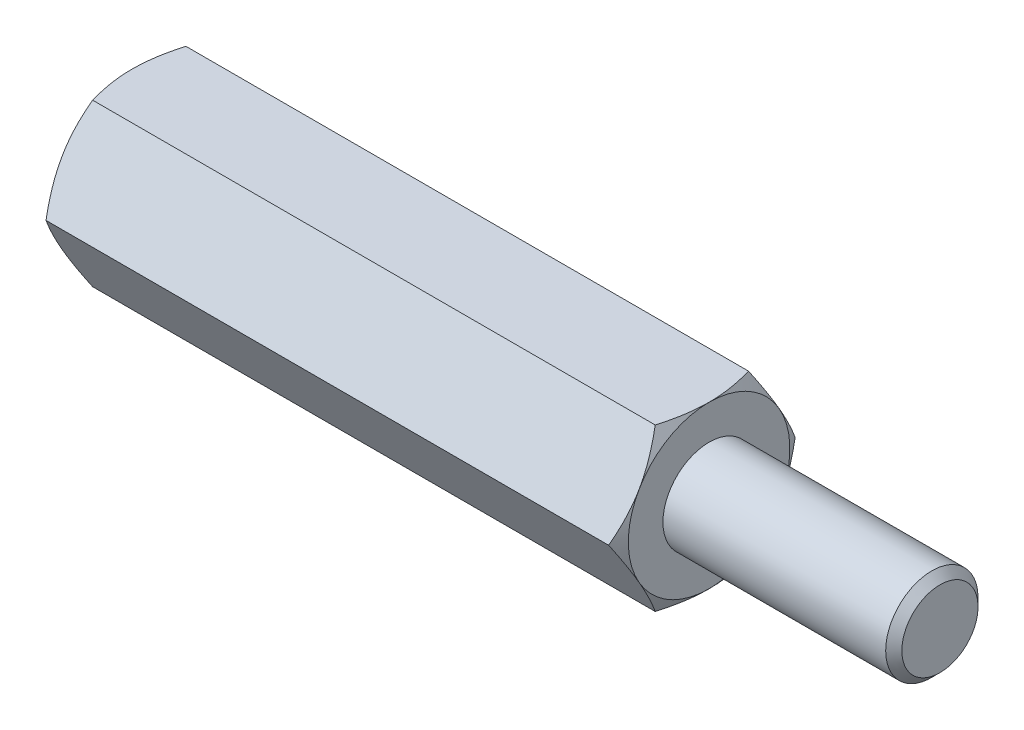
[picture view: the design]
ISO-10303-21;
HEADER;
FILE_DESCRIPTION(('STEP AP214'),'2;1');
FILE_NAME('part.step','',(''),(''),'','','');
FILE_SCHEMA(('AUTOMOTIVE_DESIGN { 1 0 10303 214 1 1 1 1 }'));
ENDSEC;
DATA;
#1=APPLICATION_CONTEXT('core data for automotive mechanical design processes');
#2=APPLICATION_PROTOCOL_DEFINITION('international standard','automotive_design',2000,#1);
#3=PRODUCT_CONTEXT('',#1,'mechanical');
#4=PRODUCT('Part','Part','',(#3));
#5=PRODUCT_RELATED_PRODUCT_CATEGORY('part','',(#4));
#6=PRODUCT_DEFINITION_FORMATION('','',#4);
#7=PRODUCT_DEFINITION_CONTEXT('part definition',#1,'design');
#8=PRODUCT_DEFINITION('design','',#6,#7);
#9=PRODUCT_DEFINITION_SHAPE('','',#8);
#10=(LENGTH_UNIT() NAMED_UNIT(*) SI_UNIT(.MILLI.,.METRE.));
#11=(NAMED_UNIT(*) PLANE_ANGLE_UNIT() SI_UNIT($,.RADIAN.));
#12=(NAMED_UNIT(*) SI_UNIT($,.STERADIAN.) SOLID_ANGLE_UNIT());
#13=UNCERTAINTY_MEASURE_WITH_UNIT(LENGTH_MEASURE(1.E-05),#10,'distance_accuracy_value','');
#14=(GEOMETRIC_REPRESENTATION_CONTEXT(3) GLOBAL_UNCERTAINTY_ASSIGNED_CONTEXT((#13)) GLOBAL_UNIT_ASSIGNED_CONTEXT((#10,
#11,#12)) REPRESENTATION_CONTEXT('',''));
#15=CARTESIAN_POINT('',(0.,0.,0.));
#16=DIRECTION('',(0.,0.,1.));
#17=DIRECTION('',(1.,0.,0.));
#18=AXIS2_PLACEMENT_3D('',#15,#16,#17);
#19=CARTESIAN_POINT('',(12.5,3.5,-2.02072594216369));
#20=DIRECTION('',(1.,0.,0.));
#21=DIRECTION('',(0.,0.,-1.));
#22=AXIS2_PLACEMENT_3D('',#19,#20,#21);
#23=PLANE('',#22);
#24=CARTESIAN_POINT('',(12.5,0.,0.));
#25=DIRECTION('',(1.,0.,0.));
#26=DIRECTION('',(0.,0.,-1.));
#27=AXIS2_PLACEMENT_3D('',#24,#25,#26);
#28=CIRCLE('',#27,3.5);
#29=CARTESIAN_POINT('',(12.5,-1.75,-3.03108891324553));
#30=VERTEX_POINT('',#29);
#31=CARTESIAN_POINT('',(12.5,1.75,-3.03108891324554));
#32=VERTEX_POINT('',#31);
#33=EDGE_CURVE('E288',#30,#32,#28,.T.);
#34=ORIENTED_EDGE('',*,*,#33,.T.);
#35=CARTESIAN_POINT('',(12.5,3.5,0.));
#36=VERTEX_POINT('',#35);
#37=EDGE_CURVE('E53',#32,#36,#28,.T.);
#38=ORIENTED_EDGE('',*,*,#37,.T.);
#39=CARTESIAN_POINT('',(12.5,1.75,3.03108891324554));
#40=VERTEX_POINT('',#39);
#41=EDGE_CURVE('E296',#36,#40,#28,.T.);
#42=ORIENTED_EDGE('',*,*,#41,.T.);
#43=CARTESIAN_POINT('',(12.5,-1.75000000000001,3.03108891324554));
#44=VERTEX_POINT('',#43);
#45=EDGE_CURVE('E301',#40,#44,#28,.T.);
#46=ORIENTED_EDGE('',*,*,#45,.T.);
#47=CARTESIAN_POINT('',(12.5,0.,0.));
#48=DIRECTION('',(-1.,0.,0.));
#49=DIRECTION('',(0.,-1.,0.));
#50=AXIS2_PLACEMENT_3D('',#47,#48,#49);
#51=CIRCLE('',#50,3.5);
#52=CARTESIAN_POINT('',(12.5,-3.5,0.));
#53=VERTEX_POINT('',#52);
#54=EDGE_CURVE('E193',#53,#44,#51,.T.);
#55=ORIENTED_EDGE('',*,*,#54,.F.);
#56=EDGE_CURVE('E61',#53,#30,#28,.T.);
#57=ORIENTED_EDGE('',*,*,#56,.T.);
#58=EDGE_LOOP('',(#34,#38,#42,#46,#55,#57));
#59=FACE_BOUND('',#58,.T.);
#60=CARTESIAN_POINT('',(12.5,0.,0.));
#61=DIRECTION('',(1.,0.,0.));
#62=DIRECTION('',(0.,0.,-1.));
#63=AXIS2_PLACEMENT_3D('',#60,#61,#62);
#64=CIRCLE('',#63,2.);
#65=CARTESIAN_POINT('',(12.5,0.,-2.));
#66=VERTEX_POINT('',#65);
#67=EDGE_CURVE('E393',#66,#66,#64,.T.);
#68=ORIENTED_EDGE('',*,*,#67,.F.);
#69=EDGE_LOOP('',(#68));
#70=FACE_BOUND('',#69,.T.);
#71=ADVANCED_FACE('F37',(#59,#70),#23,.T.);
#72=CARTESIAN_POINT('',(12.5,0.,-4.04145188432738));
#73=DIRECTION('',(0.,-0.5,0.866025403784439));
#74=DIRECTION('',(0.,-0.866025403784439,-0.5));
#75=AXIS2_PLACEMENT_3D('',#72,#73,#74);
#76=PLANE('',#75);
#77=CARTESIAN_POINT('',(12.1873259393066,-0.000200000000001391,-4.04156735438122));
#78=CARTESIAN_POINT('',(12.23861421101,0.153607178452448,-3.9527667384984));
#79=CARTESIAN_POINT('',(12.2852590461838,0.308742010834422,-3.86319960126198));
#80=CARTESIAN_POINT('',(12.3666781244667,0.621698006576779,-3.68251437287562));
#81=CARTESIAN_POINT('',(12.4014235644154,0.779524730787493,-3.59139307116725));
#82=CARTESIAN_POINT('',(12.4555099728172,1.09322221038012,-3.41027974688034));
#83=CARTESIAN_POINT('',(12.4752109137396,1.24904469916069,-3.32031559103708));
#84=CARTESIAN_POINT('',(12.4987298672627,1.56142288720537,-3.13996396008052));
#85=CARTESIAN_POINT('',(12.5025673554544,1.71797745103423,-3.04957714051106));
#86=CARTESIAN_POINT('',(12.494584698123,2.01050921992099,-2.88068384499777));
#87=CARTESIAN_POINT('',(12.4847245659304,2.1465302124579,-2.80215208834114));
#88=CARTESIAN_POINT('',(12.4534735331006,2.41768602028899,-2.64560020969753));
#89=CARTESIAN_POINT('',(12.4320719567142,2.55281989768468,-2.5675806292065));
#90=CARTESIAN_POINT('',(12.3785695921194,2.82453479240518,-2.41070596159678));
#91=CARTESIAN_POINT('',(12.3462420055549,2.96108141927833,-2.33187072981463));
#92=CARTESIAN_POINT('',(12.272871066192,3.2321380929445,-2.17537608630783));
#93=CARTESIAN_POINT('',(12.2318449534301,3.36665161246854,-2.09771466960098));
#94=CARTESIAN_POINT('',(12.1873259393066,3.5002,-2.02061047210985));
#95=B_SPLINE_CURVE_WITH_KNOTS('',3,(#77,#78,#79,#80,#81,#82,#83,#84,#85,#86,#87,#88,#89,#90,#91,
#92,#93,#94),.UNSPECIFIED.,.F.,.F.,(4,2,2,2,2,2,2,2,4),(0.,0.554793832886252,1.11092123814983,
1.65328467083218,2.19498204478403,2.6666513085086,3.13875761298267,3.6213361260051,
4.10296698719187),.UNSPECIFIED.);
#96=CARTESIAN_POINT('',(12.1873926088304,0.,-4.04145188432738));
#97=VERTEX_POINT('',#96);
#98=EDGE_CURVE('E314',#97,#32,#95,.T.);
#99=ORIENTED_EDGE('',*,*,#98,.F.);
#100=DIRECTION('',(-1.,0.,0.));
#101=VECTOR('',#100,1.);
#102=CARTESIAN_POINT('',(12.5,0.,-4.04145188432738));
#103=LINE('',#102,#101);
#104=CARTESIAN_POINT('',(-12.1873926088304,0.,-4.04145188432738));
#105=VERTEX_POINT('',#104);
#106=EDGE_CURVE('E264',#97,#105,#103,.T.);
#107=ORIENTED_EDGE('',*,*,#106,.T.);
#108=CARTESIAN_POINT('',(-12.1873259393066,3.5002,-2.02061047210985));
#109=CARTESIAN_POINT('',(-12.23861421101,3.34639282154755,-2.10941108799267));
#110=CARTESIAN_POINT('',(-12.2852590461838,3.19125798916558,-2.19897822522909));
#111=CARTESIAN_POINT('',(-12.3666781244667,2.87830199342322,-2.37966345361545));
#112=CARTESIAN_POINT('',(-12.4014235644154,2.72047526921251,-2.47078475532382));
#113=CARTESIAN_POINT('',(-12.4555099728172,2.40677778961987,-2.65189807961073));
#114=CARTESIAN_POINT('',(-12.4752109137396,2.25095530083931,-2.74186223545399));
#115=CARTESIAN_POINT('',(-12.4987298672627,1.93857711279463,-2.92221386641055));
#116=CARTESIAN_POINT('',(-12.5025673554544,1.78202254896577,-3.01260068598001));
#117=CARTESIAN_POINT('',(-12.494584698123,1.48949078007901,-3.1814939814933));
#118=CARTESIAN_POINT('',(-12.4847245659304,1.3534697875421,-3.26002573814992));
#119=CARTESIAN_POINT('',(-12.4534735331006,1.08231397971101,-3.41657761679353));
#120=CARTESIAN_POINT('',(-12.4320719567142,0.947180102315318,-3.49459719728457));
#121=CARTESIAN_POINT('',(-12.3785695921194,0.675465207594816,-3.65147186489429));
#122=CARTESIAN_POINT('',(-12.3462420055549,0.538918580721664,-3.73030709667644));
#123=CARTESIAN_POINT('',(-12.272871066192,0.267861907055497,-3.88680174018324));
#124=CARTESIAN_POINT('',(-12.2318449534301,0.133348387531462,-3.96446315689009));
#125=CARTESIAN_POINT('',(-12.1873259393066,-0.000200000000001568,-4.04156735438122));
#126=B_SPLINE_CURVE_WITH_KNOTS('',3,(#108,#109,#110,#111,#112,#113,#114,#115,#116,#117,#118,
#119,#120,#121,#122,#123,#124,#125),.UNSPECIFIED.,.F.,.F.,(4,2,2,2,2,2,2,2,4),(0.,
0.554793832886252,1.11092123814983,1.65328467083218,2.19498204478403,2.6666513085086,
3.13875761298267,3.6213361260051,4.10296698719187),.UNSPECIFIED.);
#127=CARTESIAN_POINT('',(-12.5,1.75,-3.03108891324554));
#128=VERTEX_POINT('',#127);
#129=EDGE_CURVE('E330',#128,#105,#126,.T.);
#130=ORIENTED_EDGE('',*,*,#129,.F.);
#131=CARTESIAN_POINT('',(-12.1873926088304,3.5,-2.02072594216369));
#132=VERTEX_POINT('',#131);
#133=EDGE_CURVE('E328',#132,#128,#126,.T.);
#134=ORIENTED_EDGE('',*,*,#133,.F.);
#135=DIRECTION('',(-1.,0.,0.));
#136=VECTOR('',#135,1.);
#137=CARTESIAN_POINT('',(12.5,3.5,-2.02072594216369));
#138=LINE('',#137,#136);
#139=CARTESIAN_POINT('',(12.1873926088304,3.5,-2.02072594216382));
#140=VERTEX_POINT('',#139);
#141=EDGE_CURVE('E279',#140,#132,#138,.T.);
#142=ORIENTED_EDGE('',*,*,#141,.F.);
#143=EDGE_CURVE('E229',#32,#140,#95,.T.);
#144=ORIENTED_EDGE('',*,*,#143,.F.);
#145=EDGE_LOOP('',(#99,#107,#130,#134,#142,#144));
#146=FACE_BOUND('',#145,.T.);
#147=ADVANCED_FACE('F148',(#146),#76,.F.);
#148=CARTESIAN_POINT('',(12.5,3.5,-2.02072594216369));
#149=DIRECTION('',(0.,-1.,0.));
#150=DIRECTION('',(0.,0.,-1.));
#151=AXIS2_PLACEMENT_3D('',#148,#149,#150);
#152=PLANE('',#151);
#153=CARTESIAN_POINT('',(10.7443294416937,3.5,-5.525713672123));
#154=CARTESIAN_POINT('',(10.8192813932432,3.5,-5.37200190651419));
#155=CARTESIAN_POINT('',(10.8935424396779,3.5,-5.21794762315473));
#156=CARTESIAN_POINT('',(11.0402960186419,3.5,-4.90897223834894));
#157=CARTESIAN_POINT('',(11.1127882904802,3.5,-4.75405101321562));
#158=CARTESIAN_POINT('',(11.2559617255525,3.5,-4.44240758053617));
#159=CARTESIAN_POINT('',(11.3266316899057,3.5,-4.28568021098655));
#160=CARTESIAN_POINT('',(11.4652074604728,3.5,-3.97101270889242));
#161=CARTESIAN_POINT('',(11.5331133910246,3.5,-3.81307263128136));
#162=CARTESIAN_POINT('',(11.6677143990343,3.5,-3.49026114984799));
#163=CARTESIAN_POINT('',(11.7342871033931,3.5,-3.32533845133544));
#164=CARTESIAN_POINT('',(11.8626267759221,3.5,-2.99359992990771));
#165=CARTESIAN_POINT('',(11.9243932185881,3.5,-2.82678390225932));
#166=CARTESIAN_POINT('',(12.0415700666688,3.5,-2.49127529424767));
#167=CARTESIAN_POINT('',(12.0969925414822,3.5,-2.32258697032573));
#168=CARTESIAN_POINT('',(12.1997679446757,3.5,-1.98279215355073));
#169=CARTESIAN_POINT('',(12.2471233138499,3.5,-1.81168640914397));
#170=CARTESIAN_POINT('',(12.3312987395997,3.5,-1.46793354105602));
#171=CARTESIAN_POINT('',(12.3681796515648,3.5,-1.2953015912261));
#172=CARTESIAN_POINT('',(12.4293955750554,3.5,-0.947791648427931));
#173=CARTESIAN_POINT('',(12.453731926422,3.5,-0.77291389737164));
#174=CARTESIAN_POINT('',(12.4876038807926,3.5,-0.424108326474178));
#175=CARTESIAN_POINT('',(12.497337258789,3.5,-0.250200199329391));
#176=CARTESIAN_POINT('',(12.5017053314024,3.5,0.0978233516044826));
#177=CARTESIAN_POINT('',(12.4963399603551,3.5,0.271938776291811));
#178=CARTESIAN_POINT('',(12.4750118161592,3.5,0.564711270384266));
#179=CARTESIAN_POINT('',(12.4628919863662,3.5,0.683667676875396));
#180=CARTESIAN_POINT('',(12.4323080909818,3.5,0.920767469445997));
#181=CARTESIAN_POINT('',(12.4138432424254,3.5,1.03891075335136));
#182=CARTESIAN_POINT('',(12.3498956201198,3.5,1.39193174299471));
#183=CARTESIAN_POINT('',(12.2958695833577,3.5,1.62528232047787));
#184=CARTESIAN_POINT('',(12.2014515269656,3.5,1.97433825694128));
#185=CARTESIAN_POINT('',(12.1672900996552,3.5,2.09183268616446));
#186=CARTESIAN_POINT('',(12.095234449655,3.5,2.32568238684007));
#187=CARTESIAN_POINT('',(12.0573401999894,3.5,2.44203765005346));
#188=CARTESIAN_POINT('',(11.9784421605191,3.5,2.67364238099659));
#189=CARTESIAN_POINT('',(11.9374392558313,3.5,2.78889215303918));
#190=CARTESIAN_POINT('',(11.852824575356,3.5,3.01842460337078));
#191=CARTESIAN_POINT('',(11.8092128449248,3.5,3.13270729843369));
#192=CARTESIAN_POINT('',(11.6958241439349,3.5,3.42150510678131));
#193=CARTESIAN_POINT('',(11.6245636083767,3.5,3.59543696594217));
#194=CARTESIAN_POINT('',(11.4781026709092,3.5,3.94163961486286));
#195=CARTESIAN_POINT('',(11.4029019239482,3.5,4.11391025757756));
#196=CARTESIAN_POINT('',(11.2494252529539,3.5,4.45713072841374));
#197=CARTESIAN_POINT('',(11.1711484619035,3.5,4.62808016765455));
#198=CARTESIAN_POINT('',(11.012188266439,3.5,4.9688584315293));
#199=CARTESIAN_POINT('',(10.9315047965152,3.5,5.13868722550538));
#200=CARTESIAN_POINT('',(10.6863871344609,3.5,5.64726192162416));
#201=CARTESIAN_POINT('',(10.5190975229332,3.5,5.98463020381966));
#202=CARTESIAN_POINT('',(10.1795854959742,3.5,6.65678495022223));
#203=CARTESIAN_POINT('',(10.0073639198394,3.5,6.99157184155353));
#204=CARTESIAN_POINT('',(9.67608002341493,3.5,7.62749570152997));
#205=CARTESIAN_POINT('',(9.51732992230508,3.5,7.92879562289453));
#206=CARTESIAN_POINT('',(9.19774734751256,3.5,8.53030635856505));
#207=CARTESIAN_POINT('',(9.03691477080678,3.5,8.83051711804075));
#208=CARTESIAN_POINT('',(8.71417926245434,3.5,9.42918006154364));
#209=CARTESIAN_POINT('',(8.5522810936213,3.5,9.72763481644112));
#210=CARTESIAN_POINT('',(8.2272737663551,3.5,10.3238577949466));
#211=CARTESIAN_POINT('',(8.06416469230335,3.5,10.6216260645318));
#212=CARTESIAN_POINT('',(7.90061041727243,3.5,10.9191478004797));
#213=B_SPLINE_CURVE_WITH_KNOTS('',3,(#153,#154,#155,#156,#157,#158,#159,#160,#161,#162,#163,
#164,#165,#166,#167,#168,#169,#170,#171,#172,#173,#174,#175,#176,#177,#178,#179,#180,#181,#182,
#183,#184,#185,#186,#187,#188,#189,#190,#191,#192,#193,#194,#195,#196,#197,#198,#199,#200,#201,
#202,#203,#204,#205,#206,#207,#208,#209,#210,#211,#212),.UNSPECIFIED.,.F.,.F.,(4,2,2,2,2,2,2,2,
2,2,2,2,2,2,2,2,2,2,2,2,2,2,2,2,2,2,2,2,2,4),(0.,0.513041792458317,1.02615874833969,
1.54190801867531,2.05763406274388,2.59113284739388,3.1246898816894,3.65721433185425,
4.18957737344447,4.71878103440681,5.24792816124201,5.76984197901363,6.29175806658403,
6.65030258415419,7.0088913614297,7.72642330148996,8.09346920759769,8.46051776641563,
8.82746220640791,9.19440026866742,9.7582223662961,10.3220939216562,10.8861255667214,
11.4501725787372,12.579801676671,13.7092396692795,14.730918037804,15.7526471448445,
16.771258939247,17.7898004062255),.UNSPECIFIED.);
#214=EDGE_CURVE('E227',#140,#36,#213,.T.);
#215=ORIENTED_EDGE('',*,*,#214,.F.);
#216=ORIENTED_EDGE('',*,*,#141,.T.);
#217=CARTESIAN_POINT('',(-10.7443294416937,3.5,-5.52571367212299));
#218=CARTESIAN_POINT('',(-10.8192813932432,3.5,-5.37200190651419));
#219=CARTESIAN_POINT('',(-10.8935424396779,3.5,-5.21794762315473));
#220=CARTESIAN_POINT('',(-11.0402960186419,3.5,-4.90897223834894));
#221=CARTESIAN_POINT('',(-11.1127882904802,3.5,-4.75405101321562));
#222=CARTESIAN_POINT('',(-11.2559617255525,3.5,-4.44240758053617));
#223=CARTESIAN_POINT('',(-11.3266316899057,3.5,-4.28568021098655));
#224=CARTESIAN_POINT('',(-11.4652074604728,3.5,-3.97101270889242));
#225=CARTESIAN_POINT('',(-11.5331133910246,3.5,-3.81307263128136));
#226=CARTESIAN_POINT('',(-11.6677143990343,3.5,-3.49026114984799));
#227=CARTESIAN_POINT('',(-11.7342871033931,3.5,-3.32533845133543));
#228=CARTESIAN_POINT('',(-11.8626267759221,3.5,-2.99359992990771));
#229=CARTESIAN_POINT('',(-11.9243932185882,3.5,-2.82678390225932));
#230=CARTESIAN_POINT('',(-12.0415700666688,3.5,-2.49127529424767));
#231=CARTESIAN_POINT('',(-12.0969925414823,3.5,-2.32258697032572));
#232=CARTESIAN_POINT('',(-12.1997679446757,3.5,-1.98279215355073));
#233=CARTESIAN_POINT('',(-12.2471233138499,3.5,-1.81168640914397));
#234=CARTESIAN_POINT('',(-12.3312987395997,3.5,-1.46793354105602));
#235=CARTESIAN_POINT('',(-12.3681796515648,3.5,-1.2953015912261));
#236=CARTESIAN_POINT('',(-12.4293955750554,3.5,-0.94779164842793));
#237=CARTESIAN_POINT('',(-12.453731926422,3.5,-0.772913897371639));
#238=CARTESIAN_POINT('',(-12.4876038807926,3.5,-0.424108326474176));
#239=CARTESIAN_POINT('',(-12.497337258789,3.5,-0.250200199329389));
#240=CARTESIAN_POINT('',(-12.5017053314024,3.5,0.0978233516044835));
#241=CARTESIAN_POINT('',(-12.4963399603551,3.5,0.271938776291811));
#242=CARTESIAN_POINT('',(-12.4750118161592,3.5,0.564711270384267));
#243=CARTESIAN_POINT('',(-12.4628919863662,3.5,0.683667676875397));
#244=CARTESIAN_POINT('',(-12.4323080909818,3.5,0.920767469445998));
#245=CARTESIAN_POINT('',(-12.4138432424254,3.5,1.03891075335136));
#246=CARTESIAN_POINT('',(-12.3498956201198,3.5,1.39193174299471));
#247=CARTESIAN_POINT('',(-12.2958695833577,3.5,1.62528232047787));
#248=CARTESIAN_POINT('',(-12.2014515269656,3.5,1.97433825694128));
#249=CARTESIAN_POINT('',(-12.1672900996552,3.5,2.09183268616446));
#250=CARTESIAN_POINT('',(-12.095234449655,3.5,2.32568238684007));
#251=CARTESIAN_POINT('',(-12.0573401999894,3.5,2.44203765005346));
#252=CARTESIAN_POINT('',(-11.9784421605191,3.5,2.67364238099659));
#253=CARTESIAN_POINT('',(-11.9374392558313,3.5,2.78889215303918));
#254=CARTESIAN_POINT('',(-11.852824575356,3.5,3.01842460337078));
#255=CARTESIAN_POINT('',(-11.8092128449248,3.5,3.13270729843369));
#256=CARTESIAN_POINT('',(-11.6958241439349,3.5,3.42150510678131));
#257=CARTESIAN_POINT('',(-11.6245636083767,3.5,3.59543696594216));
#258=CARTESIAN_POINT('',(-11.4781026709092,3.5,3.94163961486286));
#259=CARTESIAN_POINT('',(-11.4029019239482,3.5,4.11391025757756));
#260=CARTESIAN_POINT('',(-11.2494252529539,3.5,4.45713072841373));
#261=CARTESIAN_POINT('',(-11.1711484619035,3.5,4.62808016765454));
#262=CARTESIAN_POINT('',(-11.012188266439,3.5,4.96885843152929));
#263=CARTESIAN_POINT('',(-10.9315047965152,3.5,5.13868722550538));
#264=CARTESIAN_POINT('',(-10.6863871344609,3.5,5.64726192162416));
#265=CARTESIAN_POINT('',(-10.5190975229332,3.5,5.98463020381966));
#266=CARTESIAN_POINT('',(-10.1795854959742,3.5,6.65678495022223));
#267=CARTESIAN_POINT('',(-10.0073639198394,3.5,6.99157184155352));
#268=CARTESIAN_POINT('',(-9.67608002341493,3.5,7.62749570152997));
#269=CARTESIAN_POINT('',(-9.51732992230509,3.5,7.92879562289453));
#270=CARTESIAN_POINT('',(-9.19774734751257,3.5,8.53030635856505));
#271=CARTESIAN_POINT('',(-9.03691477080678,3.5,8.83051711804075));
#272=CARTESIAN_POINT('',(-8.71417926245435,3.5,9.42918006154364));
#273=CARTESIAN_POINT('',(-8.5522810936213,3.5,9.72763481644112));
#274=CARTESIAN_POINT('',(-8.2272737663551,3.5,10.3238577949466));
#275=CARTESIAN_POINT('',(-8.06416469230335,3.5,10.6216260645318));
#276=CARTESIAN_POINT('',(-7.90061041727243,3.5,10.9191478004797));
#277=B_SPLINE_CURVE_WITH_KNOTS('',3,(#217,#218,#219,#220,#221,#222,#223,#224,#225,#226,#227,
#228,#229,#230,#231,#232,#233,#234,#235,#236,#237,#238,#239,#240,#241,#242,#243,#244,#245,#246,
#247,#248,#249,#250,#251,#252,#253,#254,#255,#256,#257,#258,#259,#260,#261,#262,#263,#264,#265,
#266,#267,#268,#269,#270,#271,#272,#273,#274,#275,#276),.UNSPECIFIED.,.F.,.F.,(4,2,2,2,2,2,2,2,
2,2,2,2,2,2,2,2,2,2,2,2,2,2,2,2,2,2,2,2,2,4),(0.,0.513041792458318,1.02615874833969,
1.54190801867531,2.05763406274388,2.59113284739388,3.1246898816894,3.65721433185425,
4.18957737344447,4.71878103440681,5.24792816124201,5.76984197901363,6.29175806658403,
6.65030258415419,7.0088913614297,7.72642330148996,8.09346920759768,8.46051776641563,
8.8274622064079,9.19440026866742,9.75822236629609,10.3220939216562,10.8861255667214,
11.4501725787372,12.579801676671,13.7092396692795,14.730918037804,15.7526471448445,
16.7712589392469,17.7898004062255),.UNSPECIFIED.);
#278=CARTESIAN_POINT('',(-12.5,3.5,0.));
#279=VERTEX_POINT('',#278);
#280=EDGE_CURVE('E241',#279,#132,#277,.F.);
#281=ORIENTED_EDGE('',*,*,#280,.F.);
#282=CARTESIAN_POINT('',(-12.1873926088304,3.5,2.02072594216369));
#283=VERTEX_POINT('',#282);
#284=EDGE_CURVE('E249',#283,#279,#277,.F.);
#285=ORIENTED_EDGE('',*,*,#284,.F.);
#286=DIRECTION('',(-1.,0.,0.));
#287=VECTOR('',#286,1.);
#288=CARTESIAN_POINT('',(12.5,3.5,2.02072594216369));
#289=LINE('',#288,#287);
#290=CARTESIAN_POINT('',(12.1873926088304,3.5,2.02072594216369));
#291=VERTEX_POINT('',#290);
#292=EDGE_CURVE('E276',#291,#283,#289,.T.);
#293=ORIENTED_EDGE('',*,*,#292,.F.);
#294=EDGE_CURVE('E221',#36,#291,#213,.T.);
#295=ORIENTED_EDGE('',*,*,#294,.F.);
#296=EDGE_LOOP('',(#215,#216,#281,#285,#293,#295));
#297=FACE_BOUND('',#296,.T.);
#298=ADVANCED_FACE('F153',(#297),#152,.F.);
#299=CARTESIAN_POINT('',(12.5,3.5,2.02072594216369));
#300=DIRECTION('',(0.,-0.5,-0.866025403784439));
#301=DIRECTION('',(0.,0.866025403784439,-0.5));
#302=AXIS2_PLACEMENT_3D('',#299,#300,#301);
#303=PLANE('',#302);
#304=CARTESIAN_POINT('',(12.1873259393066,3.5002,2.02061047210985));
#305=CARTESIAN_POINT('',(12.23861421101,3.34639282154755,2.10941108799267));
#306=CARTESIAN_POINT('',(12.2852590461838,3.19125798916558,2.19897822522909));
#307=CARTESIAN_POINT('',(12.3666781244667,2.87830199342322,2.37966345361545));
#308=CARTESIAN_POINT('',(12.4014235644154,2.7204752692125,2.47078475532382));
#309=CARTESIAN_POINT('',(12.4555099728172,2.40677778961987,2.65189807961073));
#310=CARTESIAN_POINT('',(12.4752109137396,2.25095530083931,2.74186223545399));
#311=CARTESIAN_POINT('',(12.4987298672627,1.93857711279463,2.92221386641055));
#312=CARTESIAN_POINT('',(12.5025673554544,1.78202254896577,3.01260068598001));
#313=CARTESIAN_POINT('',(12.494584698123,1.48949078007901,3.1814939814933));
#314=CARTESIAN_POINT('',(12.4847245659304,1.35346978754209,3.26002573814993));
#315=CARTESIAN_POINT('',(12.4534735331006,1.08231397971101,3.41657761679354));
#316=CARTESIAN_POINT('',(12.4320719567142,0.947180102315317,3.49459719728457));
#317=CARTESIAN_POINT('',(12.3785695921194,0.675465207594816,3.65147186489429));
#318=CARTESIAN_POINT('',(12.3462420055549,0.538918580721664,3.73030709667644));
#319=CARTESIAN_POINT('',(12.272871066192,0.267861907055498,3.88680174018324));
#320=CARTESIAN_POINT('',(12.2318449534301,0.133348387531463,3.96446315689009));
#321=CARTESIAN_POINT('',(12.1873259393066,-0.000200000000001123,4.04156735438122));
#322=B_SPLINE_CURVE_WITH_KNOTS('',3,(#304,#305,#306,#307,#308,#309,#310,#311,#312,#313,#314,
#315,#316,#317,#318,#319,#320,#321),.UNSPECIFIED.,.F.,.F.,(4,2,2,2,2,2,2,2,4),(0.,
0.554793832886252,1.11092123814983,1.65328467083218,2.19498204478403,2.6666513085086,
3.13875761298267,3.62133612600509,4.10296698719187),.UNSPECIFIED.);
#323=EDGE_CURVE('E228',#291,#40,#322,.T.);
#324=ORIENTED_EDGE('',*,*,#323,.F.);
#325=ORIENTED_EDGE('',*,*,#292,.T.);
#326=CARTESIAN_POINT('',(-12.1873259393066,-0.000200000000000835,4.04156735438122));
#327=CARTESIAN_POINT('',(-12.23861421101,0.153607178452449,3.9527667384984));
#328=CARTESIAN_POINT('',(-12.2852590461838,0.308742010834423,3.86319960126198));
#329=CARTESIAN_POINT('',(-12.3666781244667,0.62169800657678,3.68251437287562));
#330=CARTESIAN_POINT('',(-12.4014235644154,0.779524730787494,3.59139307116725));
#331=CARTESIAN_POINT('',(-12.4555099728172,1.09322221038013,3.41027974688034));
#332=CARTESIAN_POINT('',(-12.4752109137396,1.24904469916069,3.32031559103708));
#333=CARTESIAN_POINT('',(-12.4987298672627,1.56142288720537,3.13996396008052));
#334=CARTESIAN_POINT('',(-12.5025673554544,1.71797745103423,3.04957714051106));
#335=CARTESIAN_POINT('',(-12.494584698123,2.01050921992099,2.88068384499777));
#336=CARTESIAN_POINT('',(-12.4847245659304,2.1465302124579,2.80215208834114));
#337=CARTESIAN_POINT('',(-12.4534735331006,2.41768602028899,2.64560020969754));
#338=CARTESIAN_POINT('',(-12.4320719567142,2.55281989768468,2.5675806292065));
#339=CARTESIAN_POINT('',(-12.3785695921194,2.82453479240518,2.41070596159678));
#340=CARTESIAN_POINT('',(-12.3462420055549,2.96108141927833,2.33187072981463));
#341=CARTESIAN_POINT('',(-12.272871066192,3.2321380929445,2.17537608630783));
#342=CARTESIAN_POINT('',(-12.2318449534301,3.36665161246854,2.09771466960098));
#343=CARTESIAN_POINT('',(-12.1873259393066,3.5002,2.02061047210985));
#344=B_SPLINE_CURVE_WITH_KNOTS('',3,(#326,#327,#328,#329,#330,#331,#332,#333,#334,#335,#336,
#337,#338,#339,#340,#341,#342,#343),.UNSPECIFIED.,.F.,.F.,(4,2,2,2,2,2,2,2,4),(0.,
0.554793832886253,1.11092123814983,1.65328467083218,2.19498204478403,2.6666513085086,
3.13875761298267,3.62133612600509,4.10296698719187),.UNSPECIFIED.);
#345=CARTESIAN_POINT('',(-12.5,1.75,3.03108891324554));
#346=VERTEX_POINT('',#345);
#347=EDGE_CURVE('E255',#346,#283,#344,.T.);
#348=ORIENTED_EDGE('',*,*,#347,.F.);
#349=CARTESIAN_POINT('',(-12.1873926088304,0.,4.04145188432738));
#350=VERTEX_POINT('',#349);
#351=EDGE_CURVE('E262',#350,#346,#344,.T.);
#352=ORIENTED_EDGE('',*,*,#351,.F.);
#353=DIRECTION('',(-1.,0.,0.));
#354=VECTOR('',#353,1.);
#355=CARTESIAN_POINT('',(12.5,0.,4.04145188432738));
#356=LINE('',#355,#354);
#357=CARTESIAN_POINT('',(12.1873926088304,0.,4.04145188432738));
#358=VERTEX_POINT('',#357);
#359=EDGE_CURVE('E273',#358,#350,#356,.T.);
#360=ORIENTED_EDGE('',*,*,#359,.F.);
#361=EDGE_CURVE('E215',#40,#358,#322,.T.);
#362=ORIENTED_EDGE('',*,*,#361,.F.);
#363=EDGE_LOOP('',(#324,#325,#348,#352,#360,#362));
#364=FACE_BOUND('',#363,.T.);
#365=ADVANCED_FACE('F235',(#364),#303,.F.);
#366=CARTESIAN_POINT('',(12.5,0.,4.04145188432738));
#367=DIRECTION('',(0.,0.5,-0.866025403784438));
#368=DIRECTION('',(0.,0.866025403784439,0.5));
#369=AXIS2_PLACEMENT_3D('',#366,#367,#368);
#370=PLANE('',#369);
#371=CARTESIAN_POINT('',(12.1873259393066,0.000199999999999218,4.04156735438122));
#372=CARTESIAN_POINT('',(12.23861421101,-0.15360717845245,3.9527667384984));
#373=CARTESIAN_POINT('',(12.2852590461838,-0.308742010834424,3.86319960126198));
#374=CARTESIAN_POINT('',(12.3666781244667,-0.621698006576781,3.68251437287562));
#375=CARTESIAN_POINT('',(12.4014235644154,-0.779524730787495,3.59139307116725));
#376=CARTESIAN_POINT('',(12.4555099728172,-1.09322221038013,3.41027974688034));
#377=CARTESIAN_POINT('',(12.4752109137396,-1.24904469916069,3.32031559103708));
#378=CARTESIAN_POINT('',(12.4987298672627,-1.56142288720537,3.13996396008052));
#379=CARTESIAN_POINT('',(12.5025673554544,-1.71797745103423,3.04957714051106));
#380=CARTESIAN_POINT('',(12.494584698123,-2.01050921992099,2.88068384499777));
#381=CARTESIAN_POINT('',(12.4847245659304,-2.1465302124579,2.80215208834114));
#382=CARTESIAN_POINT('',(12.4534735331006,-2.41768602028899,2.64560020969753));
#383=CARTESIAN_POINT('',(12.4320719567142,-2.55281989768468,2.5675806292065));
#384=CARTESIAN_POINT('',(12.3785695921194,-2.82453479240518,2.41070596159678));
#385=CARTESIAN_POINT('',(12.3462420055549,-2.96108141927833,2.33187072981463));
#386=CARTESIAN_POINT('',(12.272871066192,-3.2321380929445,2.17537608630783));
#387=CARTESIAN_POINT('',(12.2318449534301,-3.36665161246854,2.09771466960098));
#388=CARTESIAN_POINT('',(12.1873259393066,-3.5002,2.02061047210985));
#389=B_SPLINE_CURVE_WITH_KNOTS('',3,(#371,#372,#373,#374,#375,#376,#377,#378,#379,#380,#381,
#382,#383,#384,#385,#386,#387,#388),.UNSPECIFIED.,.F.,.F.,(4,2,2,2,2,2,2,2,4),(0.,
0.554793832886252,1.11092123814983,1.65328467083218,2.19498204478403,2.6666513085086,
3.13875761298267,3.62133612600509,4.10296698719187),.UNSPECIFIED.);
#390=EDGE_CURVE('E318',#358,#44,#389,.T.);
#391=ORIENTED_EDGE('',*,*,#390,.F.);
#392=ORIENTED_EDGE('',*,*,#359,.T.);
#393=CARTESIAN_POINT('',(-12.1873259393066,-3.5002,2.02061047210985));
#394=CARTESIAN_POINT('',(-12.23861421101,-3.34639282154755,2.10941108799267));
#395=CARTESIAN_POINT('',(-12.2852590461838,-3.19125798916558,2.19897822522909));
#396=CARTESIAN_POINT('',(-12.3666781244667,-2.87830199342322,2.37966345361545));
#397=CARTESIAN_POINT('',(-12.4014235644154,-2.72047526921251,2.47078475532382));
#398=CARTESIAN_POINT('',(-12.4555099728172,-2.40677778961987,2.65189807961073));
#399=CARTESIAN_POINT('',(-12.4752109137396,-2.25095530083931,2.74186223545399));
#400=CARTESIAN_POINT('',(-12.4987298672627,-1.93857711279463,2.92221386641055));
#401=CARTESIAN_POINT('',(-12.5025673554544,-1.78202254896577,3.01260068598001));
#402=CARTESIAN_POINT('',(-12.494584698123,-1.48949078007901,3.1814939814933));
#403=CARTESIAN_POINT('',(-12.4847245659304,-1.3534697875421,3.26002573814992));
#404=CARTESIAN_POINT('',(-12.4534735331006,-1.08231397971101,3.41657761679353));
#405=CARTESIAN_POINT('',(-12.4320719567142,-0.94718010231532,3.49459719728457));
#406=CARTESIAN_POINT('',(-12.3785695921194,-0.675465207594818,3.65147186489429));
#407=CARTESIAN_POINT('',(-12.3462420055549,-0.538918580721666,3.73030709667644));
#408=CARTESIAN_POINT('',(-12.272871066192,-0.2678619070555,3.88680174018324));
#409=CARTESIAN_POINT('',(-12.2318449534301,-0.133348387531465,3.96446315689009));
#410=CARTESIAN_POINT('',(-12.1873259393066,0.000199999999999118,4.04156735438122));
#411=B_SPLINE_CURVE_WITH_KNOTS('',3,(#393,#394,#395,#396,#397,#398,#399,#400,#401,#402,#403,
#404,#405,#406,#407,#408,#409,#410),.UNSPECIFIED.,.F.,.F.,(4,2,2,2,2,2,2,2,4),(0.,
0.554793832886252,1.11092123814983,1.65328467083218,2.19498204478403,2.6666513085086,
3.13875761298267,3.62133612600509,4.10296698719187),.UNSPECIFIED.);
#412=CARTESIAN_POINT('',(-12.5,-1.75000000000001,3.03108891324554));
#413=VERTEX_POINT('',#412);
#414=EDGE_CURVE('E263',#413,#350,#411,.T.);
#415=ORIENTED_EDGE('',*,*,#414,.F.);
#416=CARTESIAN_POINT('',(-12.1873926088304,-3.5,2.02072594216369));
#417=VERTEX_POINT('',#416);
#418=EDGE_CURVE('E250',#417,#413,#411,.T.);
#419=ORIENTED_EDGE('',*,*,#418,.F.);
#420=DIRECTION('',(-1.,0.,0.));
#421=VECTOR('',#420,1.);
#422=CARTESIAN_POINT('',(12.5,-3.5,2.02072594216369));
#423=LINE('',#422,#421);
#424=CARTESIAN_POINT('',(12.1873926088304,-3.5,2.02072594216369));
#425=VERTEX_POINT('',#424);
#426=EDGE_CURVE('E270',#425,#417,#423,.T.);
#427=ORIENTED_EDGE('',*,*,#426,.F.);
#428=EDGE_CURVE('E210',#44,#425,#389,.T.);
#429=ORIENTED_EDGE('',*,*,#428,.F.);
#430=EDGE_LOOP('',(#391,#392,#415,#419,#427,#429));
#431=FACE_BOUND('',#430,.T.);
#432=ADVANCED_FACE('F425',(#431),#370,.F.);
#433=CARTESIAN_POINT('',(12.5,-3.5,2.02072594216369));
#434=DIRECTION('',(0.,1.,0.));
#435=DIRECTION('',(0.,0.,1.));
#436=AXIS2_PLACEMENT_3D('',#433,#434,#435);
#437=PLANE('',#436);
#438=CARTESIAN_POINT('',(10.7443294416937,-3.5,-5.52571367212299));
#439=CARTESIAN_POINT('',(10.8192813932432,-3.5,-5.37200190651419));
#440=CARTESIAN_POINT('',(10.8935424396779,-3.5,-5.21794762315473));
#441=CARTESIAN_POINT('',(11.0402960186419,-3.5,-4.90897223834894));
#442=CARTESIAN_POINT('',(11.1127882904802,-3.5,-4.75405101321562));
#443=CARTESIAN_POINT('',(11.2559617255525,-3.5,-4.44240758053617));
#444=CARTESIAN_POINT('',(11.3266316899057,-3.5,-4.28568021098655));
#445=CARTESIAN_POINT('',(11.4652074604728,-3.5,-3.97101270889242));
#446=CARTESIAN_POINT('',(11.5331133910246,-3.5,-3.81307263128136));
#447=CARTESIAN_POINT('',(11.6677143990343,-3.5,-3.49026114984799));
#448=CARTESIAN_POINT('',(11.7342871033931,-3.5,-3.32533845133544));
#449=CARTESIAN_POINT('',(11.8626267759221,-3.5,-2.99359992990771));
#450=CARTESIAN_POINT('',(11.9243932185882,-3.5,-2.82678390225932));
#451=CARTESIAN_POINT('',(12.0415700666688,-3.5,-2.49127529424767));
#452=CARTESIAN_POINT('',(12.0969925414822,-3.5,-2.32258697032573));
#453=CARTESIAN_POINT('',(12.1997679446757,-3.5,-1.98279215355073));
#454=CARTESIAN_POINT('',(12.2471233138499,-3.5,-1.81168640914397));
#455=CARTESIAN_POINT('',(12.3312987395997,-3.5,-1.46793354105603));
#456=CARTESIAN_POINT('',(12.3681796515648,-3.5,-1.2953015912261));
#457=CARTESIAN_POINT('',(12.4293955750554,-3.5,-0.947791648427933));
#458=CARTESIAN_POINT('',(12.453731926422,-3.5,-0.772913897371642));
#459=CARTESIAN_POINT('',(12.4876038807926,-3.5,-0.424108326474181));
#460=CARTESIAN_POINT('',(12.497337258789,-3.5,-0.250200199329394));
#461=CARTESIAN_POINT('',(12.5017053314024,-3.5,0.0978233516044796));
#462=CARTESIAN_POINT('',(12.4963399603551,-3.5,0.271938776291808));
#463=CARTESIAN_POINT('',(12.4750118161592,-3.5,0.564711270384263));
#464=CARTESIAN_POINT('',(12.4628919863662,-3.5,0.683667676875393));
#465=CARTESIAN_POINT('',(12.4323080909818,-3.5,0.920767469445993));
#466=CARTESIAN_POINT('',(12.4138432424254,-3.5,1.03891075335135));
#467=CARTESIAN_POINT('',(12.3498956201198,-3.5,1.3919317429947));
#468=CARTESIAN_POINT('',(12.2958695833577,-3.5,1.62528232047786));
#469=CARTESIAN_POINT('',(12.2014515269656,-3.5,1.97433825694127));
#470=CARTESIAN_POINT('',(12.1672900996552,-3.5,2.09183268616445));
#471=CARTESIAN_POINT('',(12.095234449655,-3.5,2.32568238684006));
#472=CARTESIAN_POINT('',(12.0573401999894,-3.5,2.44203765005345));
#473=CARTESIAN_POINT('',(11.9784421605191,-3.5,2.67364238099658));
#474=CARTESIAN_POINT('',(11.9374392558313,-3.5,2.78889215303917));
#475=CARTESIAN_POINT('',(11.852824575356,-3.5,3.01842460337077));
#476=CARTESIAN_POINT('',(11.8092128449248,-3.5,3.13270729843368));
#477=CARTESIAN_POINT('',(11.6958241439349,-3.5,3.4215051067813));
#478=CARTESIAN_POINT('',(11.6245636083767,-3.5,3.59543696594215));
#479=CARTESIAN_POINT('',(11.4781026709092,-3.5,3.94163961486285));
#480=CARTESIAN_POINT('',(11.4029019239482,-3.5,4.11391025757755));
#481=CARTESIAN_POINT('',(11.2494252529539,-3.5,4.45713072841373));
#482=CARTESIAN_POINT('',(11.1711484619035,-3.5,4.62808016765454));
#483=CARTESIAN_POINT('',(11.0121882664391,-3.5,4.96885843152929));
#484=CARTESIAN_POINT('',(10.9315047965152,-3.5,5.13868722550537));
#485=CARTESIAN_POINT('',(10.6863871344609,-3.5,5.64726192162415));
#486=CARTESIAN_POINT('',(10.5190975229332,-3.5,5.98463020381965));
#487=CARTESIAN_POINT('',(10.1795854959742,-3.5,6.65678495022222));
#488=CARTESIAN_POINT('',(10.0073639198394,-3.5,6.99157184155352));
#489=CARTESIAN_POINT('',(9.67608002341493,-3.5,7.62749570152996));
#490=CARTESIAN_POINT('',(9.51732992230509,-3.5,7.92879562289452));
#491=CARTESIAN_POINT('',(9.19774734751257,-3.5,8.53030635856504));
#492=CARTESIAN_POINT('',(9.03691477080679,-3.5,8.83051711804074));
#493=CARTESIAN_POINT('',(8.71417926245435,-3.5,9.42918006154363));
#494=CARTESIAN_POINT('',(8.5522810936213,-3.5,9.72763481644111));
#495=CARTESIAN_POINT('',(8.22727376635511,-3.5,10.3238577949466));
#496=CARTESIAN_POINT('',(8.06416469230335,-3.5,10.6216260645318));
#497=CARTESIAN_POINT('',(7.90061041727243,-3.5,10.9191478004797));
#498=B_SPLINE_CURVE_WITH_KNOTS('',3,(#438,#439,#440,#441,#442,#443,#444,#445,#446,#447,#448,
#449,#450,#451,#452,#453,#454,#455,#456,#457,#458,#459,#460,#461,#462,#463,#464,#465,#466,#467,
#468,#469,#470,#471,#472,#473,#474,#475,#476,#477,#478,#479,#480,#481,#482,#483,#484,#485,#486,
#487,#488,#489,#490,#491,#492,#493,#494,#495,#496,#497),.UNSPECIFIED.,.F.,.F.,(4,2,2,2,2,2,2,2,
2,2,2,2,2,2,2,2,2,2,2,2,2,2,2,2,2,2,2,2,2,4),(0.,0.513041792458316,1.02615874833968,
1.5419080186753,2.05763406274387,2.59113284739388,3.1246898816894,3.65721433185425,
4.18957737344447,4.71878103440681,5.247928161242,5.76984197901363,6.29175806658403,
6.65030258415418,7.0088913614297,7.72642330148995,8.09346920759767,8.46051776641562,
8.82746220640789,9.1944002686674,9.75822236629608,10.3220939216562,10.8861255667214,
11.4501725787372,12.579801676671,13.7092396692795,14.730918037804,15.7526471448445,
16.7712589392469,17.7898004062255),.UNSPECIFIED.);
#499=EDGE_CURVE('E319',#425,#53,#498,.F.);
#500=ORIENTED_EDGE('',*,*,#499,.F.);
#501=ORIENTED_EDGE('',*,*,#426,.T.);
#502=CARTESIAN_POINT('',(-10.7443294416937,-3.5,-5.52571367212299));
#503=CARTESIAN_POINT('',(-10.8192813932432,-3.5,-5.37200190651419));
#504=CARTESIAN_POINT('',(-10.8935424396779,-3.5,-5.21794762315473));
#505=CARTESIAN_POINT('',(-11.0402960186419,-3.5,-4.90897223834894));
#506=CARTESIAN_POINT('',(-11.1127882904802,-3.5,-4.75405101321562));
#507=CARTESIAN_POINT('',(-11.2559617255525,-3.5,-4.44240758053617));
#508=CARTESIAN_POINT('',(-11.3266316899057,-3.5,-4.28568021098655));
#509=CARTESIAN_POINT('',(-11.4652074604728,-3.5,-3.97101270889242));
#510=CARTESIAN_POINT('',(-11.5331133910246,-3.5,-3.81307263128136));
#511=CARTESIAN_POINT('',(-11.6677143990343,-3.5,-3.49026114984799));
#512=CARTESIAN_POINT('',(-11.7342871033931,-3.5,-3.32533845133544));
#513=CARTESIAN_POINT('',(-11.8626267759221,-3.5,-2.99359992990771));
#514=CARTESIAN_POINT('',(-11.9243932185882,-3.5,-2.82678390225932));
#515=CARTESIAN_POINT('',(-12.0415700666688,-3.5,-2.49127529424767));
#516=CARTESIAN_POINT('',(-12.0969925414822,-3.5,-2.32258697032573));
#517=CARTESIAN_POINT('',(-12.1997679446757,-3.5,-1.98279215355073));
#518=CARTESIAN_POINT('',(-12.2471233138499,-3.5,-1.81168640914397));
#519=CARTESIAN_POINT('',(-12.3312987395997,-3.5,-1.46793354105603));
#520=CARTESIAN_POINT('',(-12.3681796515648,-3.5,-1.2953015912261));
#521=CARTESIAN_POINT('',(-12.4293955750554,-3.5,-0.947791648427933));
#522=CARTESIAN_POINT('',(-12.453731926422,-3.5,-0.772913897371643));
#523=CARTESIAN_POINT('',(-12.4876038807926,-3.5,-0.42410832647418));
#524=CARTESIAN_POINT('',(-12.497337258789,-3.5,-0.250200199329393));
#525=CARTESIAN_POINT('',(-12.5017053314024,-3.5,0.0978233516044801));
#526=CARTESIAN_POINT('',(-12.4963399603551,-3.5,0.271938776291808));
#527=CARTESIAN_POINT('',(-12.4750118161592,-3.5,0.564711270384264));
#528=CARTESIAN_POINT('',(-12.4628919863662,-3.5,0.683667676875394));
#529=CARTESIAN_POINT('',(-12.4323080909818,-3.5,0.920767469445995));
#530=CARTESIAN_POINT('',(-12.4138432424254,-3.5,1.03891075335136));
#531=CARTESIAN_POINT('',(-12.3498956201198,-3.5,1.39193174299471));
#532=CARTESIAN_POINT('',(-12.2958695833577,-3.5,1.62528232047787));
#533=CARTESIAN_POINT('',(-12.2014515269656,-3.5,1.97433825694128));
#534=CARTESIAN_POINT('',(-12.1672900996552,-3.5,2.09183268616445));
#535=CARTESIAN_POINT('',(-12.095234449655,-3.5,2.32568238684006));
#536=CARTESIAN_POINT('',(-12.0573401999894,-3.5,2.44203765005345));
#537=CARTESIAN_POINT('',(-11.9784421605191,-3.5,2.67364238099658));
#538=CARTESIAN_POINT('',(-11.9374392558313,-3.5,2.78889215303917));
#539=CARTESIAN_POINT('',(-11.852824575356,-3.5,3.01842460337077));
#540=CARTESIAN_POINT('',(-11.8092128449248,-3.5,3.13270729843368));
#541=CARTESIAN_POINT('',(-11.6958241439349,-3.5,3.4215051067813));
#542=CARTESIAN_POINT('',(-11.6245636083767,-3.5,3.59543696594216));
#543=CARTESIAN_POINT('',(-11.4781026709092,-3.5,3.94163961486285));
#544=CARTESIAN_POINT('',(-11.4029019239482,-3.5,4.11391025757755));
#545=CARTESIAN_POINT('',(-11.2494252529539,-3.5,4.45713072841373));
#546=CARTESIAN_POINT('',(-11.1711484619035,-3.5,4.62808016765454));
#547=CARTESIAN_POINT('',(-11.0121882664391,-3.5,4.96885843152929));
#548=CARTESIAN_POINT('',(-10.9315047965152,-3.5,5.13868722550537));
#549=CARTESIAN_POINT('',(-10.6863871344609,-3.5,5.64726192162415));
#550=CARTESIAN_POINT('',(-10.5190975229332,-3.5,5.98463020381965));
#551=CARTESIAN_POINT('',(-10.1795854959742,-3.5,6.65678495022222));
#552=CARTESIAN_POINT('',(-10.0073639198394,-3.5,6.99157184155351));
#553=CARTESIAN_POINT('',(-9.67608002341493,-3.5,7.62749570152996));
#554=CARTESIAN_POINT('',(-9.51732992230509,-3.5,7.92879562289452));
#555=CARTESIAN_POINT('',(-9.19774734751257,-3.5,8.53030635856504));
#556=CARTESIAN_POINT('',(-9.03691477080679,-3.5,8.83051711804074));
#557=CARTESIAN_POINT('',(-8.71417926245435,-3.5,9.42918006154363));
#558=CARTESIAN_POINT('',(-8.55228109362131,-3.5,9.72763481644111));
#559=CARTESIAN_POINT('',(-8.22727376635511,-3.5,10.3238577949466));
#560=CARTESIAN_POINT('',(-8.06416469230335,-3.5,10.6216260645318));
#561=CARTESIAN_POINT('',(-7.90061041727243,-3.5,10.9191478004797));
#562=B_SPLINE_CURVE_WITH_KNOTS('',3,(#502,#503,#504,#505,#506,#507,#508,#509,#510,#511,#512,
#513,#514,#515,#516,#517,#518,#519,#520,#521,#522,#523,#524,#525,#526,#527,#528,#529,#530,#531,
#532,#533,#534,#535,#536,#537,#538,#539,#540,#541,#542,#543,#544,#545,#546,#547,#548,#549,#550,
#551,#552,#553,#554,#555,#556,#557,#558,#559,#560,#561),.UNSPECIFIED.,.F.,.F.,(4,2,2,2,2,2,2,2,
2,2,2,2,2,2,2,2,2,2,2,2,2,2,2,2,2,2,2,2,2,4),(0.,0.513041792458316,1.02615874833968,
1.5419080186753,2.05763406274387,2.59113284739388,3.1246898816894,3.65721433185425,
4.18957737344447,4.71878103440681,5.247928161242,5.76984197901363,6.29175806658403,
6.65030258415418,7.0088913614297,7.72642330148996,8.09346920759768,8.46051776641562,
8.82746220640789,9.1944002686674,9.75822236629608,10.3220939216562,10.8861255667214,
11.4501725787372,12.579801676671,13.7092396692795,14.730918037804,15.7526471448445,
16.7712589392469,17.7898004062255),.UNSPECIFIED.);
#563=CARTESIAN_POINT('',(-12.5,-3.5,0.));
#564=VERTEX_POINT('',#563);
#565=EDGE_CURVE('E329',#564,#417,#562,.T.);
#566=ORIENTED_EDGE('',*,*,#565,.F.);
#567=CARTESIAN_POINT('',(-12.1873926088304,-3.5,-2.02072594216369));
#568=VERTEX_POINT('',#567);
#569=EDGE_CURVE('E336',#568,#564,#562,.T.);
#570=ORIENTED_EDGE('',*,*,#569,.F.);
#571=DIRECTION('',(-1.,0.,0.));
#572=VECTOR('',#571,1.);
#573=CARTESIAN_POINT('',(12.5,-3.5,-2.02072594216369));
#574=LINE('',#573,#572);
#575=CARTESIAN_POINT('',(12.1873926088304,-3.5,-2.02072594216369));
#576=VERTEX_POINT('',#575);
#577=EDGE_CURVE('E267',#576,#568,#574,.T.);
#578=ORIENTED_EDGE('',*,*,#577,.F.);
#579=EDGE_CURVE('E195',#53,#576,#498,.F.);
#580=ORIENTED_EDGE('',*,*,#579,.F.);
#581=EDGE_LOOP('',(#500,#501,#566,#570,#578,#580));
#582=FACE_BOUND('',#581,.T.);
#583=ADVANCED_FACE('F172',(#582),#437,.F.);
#584=CARTESIAN_POINT('',(12.5,-3.5,-2.02072594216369));
#585=DIRECTION('',(0.,0.5,0.866025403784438));
#586=DIRECTION('',(0.,-0.866025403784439,0.5));
#587=AXIS2_PLACEMENT_3D('',#584,#585,#586);
#588=PLANE('',#587);
#589=CARTESIAN_POINT('',(12.1873259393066,-3.5002,-2.02061047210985));
#590=CARTESIAN_POINT('',(12.23861421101,-3.34639282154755,-2.10941108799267));
#591=CARTESIAN_POINT('',(12.2852590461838,-3.19125798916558,-2.19897822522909));
#592=CARTESIAN_POINT('',(12.3666781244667,-2.87830199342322,-2.37966345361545));
#593=CARTESIAN_POINT('',(12.4014235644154,-2.72047526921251,-2.47078475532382));
#594=CARTESIAN_POINT('',(12.4555099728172,-2.40677778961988,-2.65189807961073));
#595=CARTESIAN_POINT('',(12.4752109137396,-2.25095530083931,-2.74186223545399));
#596=CARTESIAN_POINT('',(12.4987298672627,-1.93857711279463,-2.92221386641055));
#597=CARTESIAN_POINT('',(12.5025673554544,-1.78202254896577,-3.01260068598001));
#598=CARTESIAN_POINT('',(12.494584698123,-1.48949078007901,-3.1814939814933));
#599=CARTESIAN_POINT('',(12.4847245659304,-1.3534697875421,-3.26002573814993));
#600=CARTESIAN_POINT('',(12.4534735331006,-1.08231397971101,-3.41657761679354));
#601=CARTESIAN_POINT('',(12.4320719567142,-0.94718010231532,-3.49459719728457));
#602=CARTESIAN_POINT('',(12.3785695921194,-0.675465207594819,-3.65147186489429));
#603=CARTESIAN_POINT('',(12.3462420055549,-0.538918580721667,-3.73030709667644));
#604=CARTESIAN_POINT('',(12.272871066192,-0.2678619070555,-3.88680174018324));
#605=CARTESIAN_POINT('',(12.2318449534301,-0.133348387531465,-3.96446315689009));
#606=CARTESIAN_POINT('',(12.1873259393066,0.000199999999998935,-4.04156735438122));
#607=B_SPLINE_CURVE_WITH_KNOTS('',3,(#589,#590,#591,#592,#593,#594,#595,#596,#597,#598,#599,
#600,#601,#602,#603,#604,#605,#606),.UNSPECIFIED.,.F.,.F.,(4,2,2,2,2,2,2,2,4),(0.,
0.554793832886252,1.11092123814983,1.65328467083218,2.19498204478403,2.6666513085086,
3.13875761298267,3.62133612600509,4.10296698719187),.UNSPECIFIED.);
#608=EDGE_CURVE('E192',#576,#30,#607,.T.);
#609=ORIENTED_EDGE('',*,*,#608,.F.);
#610=ORIENTED_EDGE('',*,*,#577,.T.);
#611=CARTESIAN_POINT('',(-12.1873259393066,0.000199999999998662,-4.04156735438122));
#612=CARTESIAN_POINT('',(-12.23861421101,-0.153607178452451,-3.9527667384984));
#613=CARTESIAN_POINT('',(-12.2852590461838,-0.308742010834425,-3.86319960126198));
#614=CARTESIAN_POINT('',(-12.3666781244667,-0.621698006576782,-3.68251437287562));
#615=CARTESIAN_POINT('',(-12.4014235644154,-0.779524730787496,-3.59139307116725));
#616=CARTESIAN_POINT('',(-12.4555099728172,-1.09322221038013,-3.41027974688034));
#617=CARTESIAN_POINT('',(-12.4752109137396,-1.24904469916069,-3.32031559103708));
#618=CARTESIAN_POINT('',(-12.4987298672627,-1.56142288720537,-3.13996396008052));
#619=CARTESIAN_POINT('',(-12.5025673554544,-1.71797745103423,-3.04957714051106));
#620=CARTESIAN_POINT('',(-12.494584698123,-2.01050921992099,-2.88068384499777));
#621=CARTESIAN_POINT('',(-12.4847245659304,-2.1465302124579,-2.80215208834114));
#622=CARTESIAN_POINT('',(-12.4534735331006,-2.41768602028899,-2.64560020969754));
#623=CARTESIAN_POINT('',(-12.4320719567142,-2.55281989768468,-2.5675806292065));
#624=CARTESIAN_POINT('',(-12.3785695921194,-2.82453479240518,-2.41070596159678));
#625=CARTESIAN_POINT('',(-12.3462420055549,-2.96108141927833,-2.33187072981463));
#626=CARTESIAN_POINT('',(-12.272871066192,-3.2321380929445,-2.17537608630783));
#627=CARTESIAN_POINT('',(-12.2318449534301,-3.36665161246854,-2.09771466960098));
#628=CARTESIAN_POINT('',(-12.1873259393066,-3.5002,-2.02061047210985));
#629=B_SPLINE_CURVE_WITH_KNOTS('',3,(#611,#612,#613,#614,#615,#616,#617,#618,#619,#620,#621,
#622,#623,#624,#625,#626,#627,#628),.UNSPECIFIED.,.F.,.F.,(4,2,2,2,2,2,2,2,4),(0.,
0.554793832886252,1.11092123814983,1.65328467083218,2.19498204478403,2.66665130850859,
3.13875761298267,3.62133612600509,4.10296698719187),.UNSPECIFIED.);
#630=CARTESIAN_POINT('',(-12.5,-1.75,-3.03108891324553));
#631=VERTEX_POINT('',#630);
#632=EDGE_CURVE('E178',#631,#568,#629,.T.);
#633=ORIENTED_EDGE('',*,*,#632,.F.);
#634=EDGE_CURVE('E345',#105,#631,#629,.T.);
#635=ORIENTED_EDGE('',*,*,#634,.F.);
#636=ORIENTED_EDGE('',*,*,#106,.F.);
#637=EDGE_CURVE('E185',#30,#97,#607,.T.);
#638=ORIENTED_EDGE('',*,*,#637,.F.);
#639=EDGE_LOOP('',(#609,#610,#633,#635,#636,#638));
#640=FACE_BOUND('',#639,.T.);
#641=ADVANCED_FACE('F167',(#640),#588,.F.);
#642=CARTESIAN_POINT('',(-12.5,0.,0.));
#643=DIRECTION('',(1.,0.,0.));
#644=DIRECTION('',(0.,1.,0.));
#645=AXIS2_PLACEMENT_3D('',#642,#643,#644);
#646=CONICAL_SURFACE('',#645,3.5,1.0471975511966);
#647=ORIENTED_EDGE('',*,*,#129,.T.);
#648=ORIENTED_EDGE('',*,*,#634,.T.);
#649=CARTESIAN_POINT('',(-12.5,0.,0.));
#650=DIRECTION('',(1.,0.,0.));
#651=DIRECTION('',(0.,0.,-1.));
#652=AXIS2_PLACEMENT_3D('',#649,#650,#651);
#653=CIRCLE('',#652,3.5);
#654=EDGE_CURVE('E282',#631,#128,#653,.T.);
#655=ORIENTED_EDGE('',*,*,#654,.T.);
#656=EDGE_LOOP('',(#647,#648,#655));
#657=FACE_BOUND('',#656,.T.);
#658=ADVANCED_FACE('F171',(#657),#646,.T.);
#659=ORIENTED_EDGE('',*,*,#569,.T.);
#660=EDGE_CURVE('E286',#564,#631,#653,.T.);
#661=ORIENTED_EDGE('',*,*,#660,.T.);
#662=ORIENTED_EDGE('',*,*,#632,.T.);
#663=EDGE_LOOP('',(#659,#661,#662));
#664=FACE_BOUND('',#663,.T.);
#665=ADVANCED_FACE('F427',(#664),#646,.T.);
#666=ORIENTED_EDGE('',*,*,#418,.T.);
#667=CARTESIAN_POINT('',(-12.5,0.,0.));
#668=DIRECTION('',(-1.,0.,0.));
#669=DIRECTION('',(0.,-1.,0.));
#670=AXIS2_PLACEMENT_3D('',#667,#668,#669);
#671=CIRCLE('',#670,3.5);
#672=EDGE_CURVE('E356',#564,#413,#671,.T.);
#673=ORIENTED_EDGE('',*,*,#672,.F.);
#674=ORIENTED_EDGE('',*,*,#565,.T.);
#675=EDGE_LOOP('',(#666,#673,#674));
#676=FACE_BOUND('',#675,.T.);
#677=ADVANCED_FACE('F422',(#676),#646,.T.);
#678=ORIENTED_EDGE('',*,*,#351,.T.);
#679=EDGE_CURVE('E320',#346,#413,#653,.T.);
#680=ORIENTED_EDGE('',*,*,#679,.T.);
#681=ORIENTED_EDGE('',*,*,#414,.T.);
#682=EDGE_LOOP('',(#678,#680,#681));
#683=FACE_BOUND('',#682,.T.);
#684=ADVANCED_FACE('F158',(#683),#646,.T.);
#685=ORIENTED_EDGE('',*,*,#347,.T.);
#686=ORIENTED_EDGE('',*,*,#284,.T.);
#687=EDGE_CURVE('E323',#279,#346,#653,.T.);
#688=ORIENTED_EDGE('',*,*,#687,.T.);
#689=EDGE_LOOP('',(#685,#686,#688));
#690=FACE_BOUND('',#689,.T.);
#691=ADVANCED_FACE('F402',(#690),#646,.T.);
#692=ORIENTED_EDGE('',*,*,#280,.T.);
#693=ORIENTED_EDGE('',*,*,#133,.T.);
#694=EDGE_CURVE('E287',#128,#279,#653,.T.);
#695=ORIENTED_EDGE('',*,*,#694,.T.);
#696=EDGE_LOOP('',(#692,#693,#695));
#697=FACE_BOUND('',#696,.T.);
#698=ADVANCED_FACE('F165',(#697),#646,.T.);
#699=CARTESIAN_POINT('',(-12.5,3.5,-2.02072594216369));
#700=DIRECTION('',(1.,0.,0.));
#701=DIRECTION('',(0.,0.,-1.));
#702=AXIS2_PLACEMENT_3D('',#699,#700,#701);
#703=PLANE('',#702);
#704=CARTESIAN_POINT('',(-12.5,0.,0.));
#705=DIRECTION('',(-1.,0.,0.));
#706=DIRECTION('',(0.,0.,1.));
#707=AXIS2_PLACEMENT_3D('',#704,#705,#706);
#708=CIRCLE('',#707,1.65);
#709=CARTESIAN_POINT('',(-12.5,0.,1.65));
#710=VERTEX_POINT('',#709);
#711=EDGE_CURVE('E384',#710,#710,#708,.T.);
#712=ORIENTED_EDGE('',*,*,#711,.F.);
#713=EDGE_LOOP('',(#712));
#714=FACE_BOUND('',#713,.T.);
#715=ORIENTED_EDGE('',*,*,#694,.F.);
#716=ORIENTED_EDGE('',*,*,#654,.F.);
#717=ORIENTED_EDGE('',*,*,#660,.F.);
#718=ORIENTED_EDGE('',*,*,#672,.T.);
#719=ORIENTED_EDGE('',*,*,#679,.F.);
#720=ORIENTED_EDGE('',*,*,#687,.F.);
#721=EDGE_LOOP('',(#715,#716,#717,#718,#719,#720));
#722=FACE_BOUND('',#721,.T.);
#723=ADVANCED_FACE('F161',(#714,#722),#703,.F.);
#724=CARTESIAN_POINT('',(12.5,0.,0.));
#725=DIRECTION('',(-1.,0.,0.));
#726=DIRECTION('',(0.,1.,0.));
#727=AXIS2_PLACEMENT_3D('',#724,#725,#726);
#728=CONICAL_SURFACE('',#727,3.5,1.0471975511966);
#729=ORIENTED_EDGE('',*,*,#98,.T.);
#730=ORIENTED_EDGE('',*,*,#33,.F.);
#731=ORIENTED_EDGE('',*,*,#637,.T.);
#732=EDGE_LOOP('',(#729,#730,#731));
#733=FACE_BOUND('',#732,.T.);
#734=ADVANCED_FACE('F164',(#733),#728,.T.);
#735=ORIENTED_EDGE('',*,*,#579,.T.);
#736=ORIENTED_EDGE('',*,*,#608,.T.);
#737=ORIENTED_EDGE('',*,*,#56,.F.);
#738=EDGE_LOOP('',(#735,#736,#737));
#739=FACE_BOUND('',#738,.T.);
#740=ADVANCED_FACE('F202',(#739),#728,.T.);
#741=ORIENTED_EDGE('',*,*,#428,.T.);
#742=ORIENTED_EDGE('',*,*,#499,.T.);
#743=ORIENTED_EDGE('',*,*,#54,.T.);
#744=EDGE_LOOP('',(#741,#742,#743));
#745=FACE_BOUND('',#744,.T.);
#746=ADVANCED_FACE('F521',(#745),#728,.T.);
#747=ORIENTED_EDGE('',*,*,#361,.T.);
#748=ORIENTED_EDGE('',*,*,#390,.T.);
#749=ORIENTED_EDGE('',*,*,#45,.F.);
#750=EDGE_LOOP('',(#747,#748,#749));
#751=FACE_BOUND('',#750,.T.);
#752=ADVANCED_FACE('F514',(#751),#728,.T.);
#753=ORIENTED_EDGE('',*,*,#294,.T.);
#754=ORIENTED_EDGE('',*,*,#323,.T.);
#755=ORIENTED_EDGE('',*,*,#41,.F.);
#756=EDGE_LOOP('',(#753,#754,#755));
#757=FACE_BOUND('',#756,.T.);
#758=ADVANCED_FACE('F378',(#757),#728,.T.);
#759=ORIENTED_EDGE('',*,*,#143,.T.);
#760=ORIENTED_EDGE('',*,*,#214,.T.);
#761=ORIENTED_EDGE('',*,*,#37,.F.);
#762=EDGE_LOOP('',(#759,#760,#761));
#763=FACE_BOUND('',#762,.T.);
#764=ADVANCED_FACE('F143',(#763),#728,.T.);
#765=CARTESIAN_POINT('',(-2.5,0.,0.));
#766=DIRECTION('',(-1.,0.,0.));
#767=DIRECTION('',(0.,0.,1.));
#768=AXIS2_PLACEMENT_3D('',#765,#766,#767);
#769=CYLINDRICAL_SURFACE('',#768,1.65);
#770=CARTESIAN_POINT('',(-2.5,0.,0.));
#771=DIRECTION('',(1.,0.,0.));
#772=DIRECTION('',(0.,1.,0.));
#773=AXIS2_PLACEMENT_3D('',#770,#771,#772);
#774=CIRCLE('',#773,1.65);
#775=CARTESIAN_POINT('',(-2.5,1.65,0.));
#776=VERTEX_POINT('',#775);
#777=EDGE_CURVE('E386',#776,#776,#774,.T.);
#778=ORIENTED_EDGE('',*,*,#777,.T.);
#779=EDGE_LOOP('',(#778));
#780=FACE_BOUND('',#779,.T.);
#781=ORIENTED_EDGE('',*,*,#711,.T.);
#782=EDGE_LOOP('',(#781));
#783=FACE_BOUND('',#782,.T.);
#784=ADVANCED_FACE('F133',(#780,#783),#769,.F.);
#785=CARTESIAN_POINT('',(-1.54737205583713,0.,0.));
#786=DIRECTION('',(-1.,0.,0.));
#787=DIRECTION('',(0.,-1.,0.));
#788=AXIS2_PLACEMENT_3D('',#785,#786,#787);
#789=CONICAL_SURFACE('',#788,0.,1.0471975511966);
#790=ORIENTED_EDGE('',*,*,#777,.F.);
#791=EDGE_LOOP('',(#790));
#792=FACE_BOUND('',#791,.T.);
#793=CARTESIAN_POINT('',(-1.54737205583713,0.,0.));
#794=VERTEX_POINT('',#793);
#795=VERTEX_LOOP('',#794);
#796=FACE_BOUND('',#795,.T.);
#797=ADVANCED_FACE('F130',(#792,#796),#789,.F.);
#798=CARTESIAN_POINT('',(22.5,0.,0.));
#799=DIRECTION('',(-1.,0.,0.));
#800=DIRECTION('',(0.,0.,1.));
#801=AXIS2_PLACEMENT_3D('',#798,#799,#800);
#802=CYLINDRICAL_SURFACE('',#801,2.);
#803=CARTESIAN_POINT('',(22.15,0.,0.));
#804=DIRECTION('',(1.,0.,0.));
#805=DIRECTION('',(0.,0.,-1.));
#806=AXIS2_PLACEMENT_3D('',#803,#804,#805);
#807=CIRCLE('',#806,2.);
#808=CARTESIAN_POINT('',(22.15,0.,2.));
#809=VERTEX_POINT('',#808);
#810=EDGE_CURVE('E11',#809,#809,#807,.F.);
#811=ORIENTED_EDGE('',*,*,#810,.T.);
#812=EDGE_LOOP('',(#811));
#813=FACE_BOUND('',#812,.T.);
#814=ORIENTED_EDGE('',*,*,#67,.T.);
#815=EDGE_LOOP('',(#814));
#816=FACE_BOUND('',#815,.T.);
#817=ADVANCED_FACE('F132',(#813,#816),#802,.T.);
#818=CARTESIAN_POINT('',(22.5,0.,0.));
#819=DIRECTION('',(1.,0.,0.));
#820=DIRECTION('',(0.,0.,-1.));
#821=AXIS2_PLACEMENT_3D('',#818,#819,#820);
#822=PLANE('',#821);
#823=CARTESIAN_POINT('',(22.5,0.,0.));
#824=DIRECTION('',(1.,0.,0.));
#825=DIRECTION('',(0.,0.,-1.));
#826=AXIS2_PLACEMENT_3D('',#823,#824,#825);
#827=CIRCLE('',#826,1.65);
#828=CARTESIAN_POINT('',(22.5,0.,1.65));
#829=VERTEX_POINT('',#828);
#830=EDGE_CURVE('E46',#829,#829,#827,.T.);
#831=ORIENTED_EDGE('',*,*,#830,.T.);
#832=EDGE_LOOP('',(#831));
#833=FACE_BOUND('',#832,.T.);
#834=ADVANCED_FACE('F140',(#833),#822,.T.);
#835=CARTESIAN_POINT('',(22.5,0.,0.));
#836=DIRECTION('',(-1.,0.,0.));
#837=DIRECTION('',(0.,0.,1.));
#838=AXIS2_PLACEMENT_3D('',#835,#836,#837);
#839=CONICAL_SURFACE('',#838,1.65,0.785398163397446);
#840=CARTESIAN_POINT('',(22.15,0.,2.));
#841=CARTESIAN_POINT('',(22.1536458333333,0.,1.99635416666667));
#842=CARTESIAN_POINT('',(22.1572916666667,0.,1.99270833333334));
#843=CARTESIAN_POINT('',(22.1645833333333,0.,1.98541666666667));
#844=CARTESIAN_POINT('',(22.1682291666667,0.,1.98177083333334));
#845=CARTESIAN_POINT('',(22.1755208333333,0.,1.97447916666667));
#846=CARTESIAN_POINT('',(22.1791666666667,0.,1.97083333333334));
#847=CARTESIAN_POINT('',(22.1864583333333,0.,1.96354166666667));
#848=CARTESIAN_POINT('',(22.1901041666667,0.,1.95989583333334));
#849=CARTESIAN_POINT('',(22.1973958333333,0.,1.95260416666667));
#850=CARTESIAN_POINT('',(22.2010416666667,0.,1.94895833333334));
#851=CARTESIAN_POINT('',(22.2083333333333,0.,1.94166666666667));
#852=CARTESIAN_POINT('',(22.2119791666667,0.,1.93802083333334));
#853=CARTESIAN_POINT('',(22.2192708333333,0.,1.93072916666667));
#854=CARTESIAN_POINT('',(22.2229166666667,0.,1.92708333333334));
#855=CARTESIAN_POINT('',(22.2302083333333,0.,1.91979166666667));
#856=CARTESIAN_POINT('',(22.2338541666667,0.,1.91614583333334));
#857=CARTESIAN_POINT('',(22.2411458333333,0.,1.90885416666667));
#858=CARTESIAN_POINT('',(22.2447916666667,0.,1.90520833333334));
#859=CARTESIAN_POINT('',(22.2520833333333,0.,1.89791666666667));
#860=CARTESIAN_POINT('',(22.2557291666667,0.,1.89427083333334));
#861=CARTESIAN_POINT('',(22.2630208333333,0.,1.88697916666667));
#862=CARTESIAN_POINT('',(22.2666666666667,0.,1.88333333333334));
#863=CARTESIAN_POINT('',(22.2739583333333,0.,1.87604166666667));
#864=CARTESIAN_POINT('',(22.2776041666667,0.,1.87239583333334));
#865=CARTESIAN_POINT('',(22.2848958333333,0.,1.86510416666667));
#866=CARTESIAN_POINT('',(22.2885416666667,0.,1.86145833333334));
#867=CARTESIAN_POINT('',(22.2958333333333,0.,1.85416666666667));
#868=CARTESIAN_POINT('',(22.2994791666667,0.,1.85052083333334));
#869=CARTESIAN_POINT('',(22.3067708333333,0.,1.84322916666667));
#870=CARTESIAN_POINT('',(22.3104166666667,0.,1.83958333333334));
#871=CARTESIAN_POINT('',(22.3177083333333,0.,1.83229166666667));
#872=CARTESIAN_POINT('',(22.3213541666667,0.,1.82864583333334));
#873=CARTESIAN_POINT('',(22.3286458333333,0.,1.82135416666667));
#874=CARTESIAN_POINT('',(22.3322916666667,0.,1.81770833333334));
#875=CARTESIAN_POINT('',(22.3395833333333,0.,1.81041666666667));
#876=CARTESIAN_POINT('',(22.3432291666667,0.,1.80677083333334));
#877=CARTESIAN_POINT('',(22.3505208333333,0.,1.79947916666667));
#878=CARTESIAN_POINT('',(22.3541666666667,0.,1.79583333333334));
#879=CARTESIAN_POINT('',(22.3614583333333,0.,1.78854166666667));
#880=CARTESIAN_POINT('',(22.3651041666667,0.,1.78489583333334));
#881=CARTESIAN_POINT('',(22.3723958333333,0.,1.77760416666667));
#882=CARTESIAN_POINT('',(22.3760416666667,0.,1.77395833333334));
#883=CARTESIAN_POINT('',(22.3833333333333,0.,1.76666666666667));
#884=CARTESIAN_POINT('',(22.3869791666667,0.,1.76302083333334));
#885=CARTESIAN_POINT('',(22.3942708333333,0.,1.75572916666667));
#886=CARTESIAN_POINT('',(22.3979166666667,0.,1.75208333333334));
#887=CARTESIAN_POINT('',(22.4052083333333,0.,1.74479166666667));
#888=CARTESIAN_POINT('',(22.4088541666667,0.,1.74114583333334));
#889=CARTESIAN_POINT('',(22.4161458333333,0.,1.73385416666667));
#890=CARTESIAN_POINT('',(22.4197916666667,0.,1.73020833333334));
#891=CARTESIAN_POINT('',(22.4270833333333,0.,1.72291666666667));
#892=CARTESIAN_POINT('',(22.4307291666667,0.,1.71927083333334));
#893=CARTESIAN_POINT('',(22.4380208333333,0.,1.71197916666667));
#894=CARTESIAN_POINT('',(22.4416666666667,0.,1.70833333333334));
#895=CARTESIAN_POINT('',(22.4489583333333,0.,1.70104166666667));
#896=CARTESIAN_POINT('',(22.4526041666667,0.,1.69739583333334));
#897=CARTESIAN_POINT('',(22.4598958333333,0.,1.69010416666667));
#898=CARTESIAN_POINT('',(22.4635416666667,0.,1.68645833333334));
#899=CARTESIAN_POINT('',(22.4708333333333,0.,1.67916666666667));
#900=CARTESIAN_POINT('',(22.4744791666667,0.,1.67552083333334));
#901=CARTESIAN_POINT('',(22.4817708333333,0.,1.66822916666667));
#902=CARTESIAN_POINT('',(22.4854166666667,0.,1.66458333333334));
#903=CARTESIAN_POINT('',(22.4927083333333,0.,1.65729166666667));
#904=CARTESIAN_POINT('',(22.4963541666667,0.,1.65364583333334));
#905=CARTESIAN_POINT('',(22.5,0.,1.65));
#906=B_SPLINE_CURVE_WITH_KNOTS('',3,(#840,#841,#842,#843,#844,#845,#846,#847,#848,#849,#850,
#851,#852,#853,#854,#855,#856,#857,#858,#859,#860,#861,#862,#863,#864,#865,#866,#867,#868,#869,
#870,#871,#872,#873,#874,#875,#876,#877,#878,#879,#880,#881,#882,#883,#884,#885,#886,#887,#888,
#889,#890,#891,#892,#893,#894,#895,#896,#897,#898,#899,#900,#901,#902,#903,#904,#905),
.UNSPECIFIED.,.F.,.F.,(4,2,2,2,2,2,2,2,2,2,2,2,2,2,2,2,2,2,2,2,2,2,2,2,2,2,2,2,2,2,2,2,4),(0.,
0.0154679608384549,0.0309359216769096,0.046403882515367,0.0618718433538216,0.0773398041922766,
0.092807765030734,0.108275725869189,0.123743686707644,0.139211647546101,0.154679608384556,
0.170147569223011,0.185615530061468,0.201083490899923,0.216551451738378,0.232019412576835,
0.24748737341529,0.262955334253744,0.278423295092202,0.293891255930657,0.309359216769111,
0.324827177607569,0.340295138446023,0.355763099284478,0.371231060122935,0.38669902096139,
0.402166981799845,0.417634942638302,0.433102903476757,0.448570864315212,0.464038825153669,
0.479506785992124,0.494974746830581),.UNSPECIFIED.);
#907=EDGE_CURVE('BSEAM39',#809,#829,#906,.T.);
#908=ORIENTED_EDGE('',*,*,#810,.F.);
#909=ORIENTED_EDGE('',*,*,#830,.F.);
#910=ORIENTED_EDGE('',*,*,#907,.T.);
#911=ORIENTED_EDGE('',*,*,#907,.F.);
#912=EDGE_LOOP('',(#908,#910,#909,#911));
#913=FACE_BOUND('',#912,.T.);
#914=ADVANCED_FACE('F39',(#913),#839,.T.);
#915=CLOSED_SHELL('',(#71,#147,#298,#365,#432,#583,#641,#658,#665,#677,#684,#691,#698,#723,#734,
#740,#746,#752,#758,#764,#784,#797,#817,#834,#914));
#916=MANIFOLD_SOLID_BREP('B2',#915);
#917=ADVANCED_BREP_SHAPE_REPRESENTATION('',(#18,#916),#14);
#918=SHAPE_DEFINITION_REPRESENTATION(#9,#917);
ENDSEC;
END-ISO-10303-21;
